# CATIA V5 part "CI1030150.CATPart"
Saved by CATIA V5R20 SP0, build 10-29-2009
Part number: CI1030150
Bounding box of the stored display mesh (mm): x -29 to 29, y -25.76 to 195, z -32.028 to 34.295
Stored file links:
  C:\Users\Raffaele\Desktop\3D X SITO CF\BOLEX\19-INCLINED ASSEMBLY REF_CI\CI1030150.CATPart

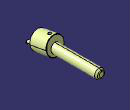
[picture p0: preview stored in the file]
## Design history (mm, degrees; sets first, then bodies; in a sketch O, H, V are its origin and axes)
Set1
  DatumSurface1 to DatumSurface16 "MANIFOLD_SOLID_BREP #395"
  DatumSurface17 to DatumSurface39 "MANIFOLD_SOLID_BREP #1144"
Body1 (main body)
